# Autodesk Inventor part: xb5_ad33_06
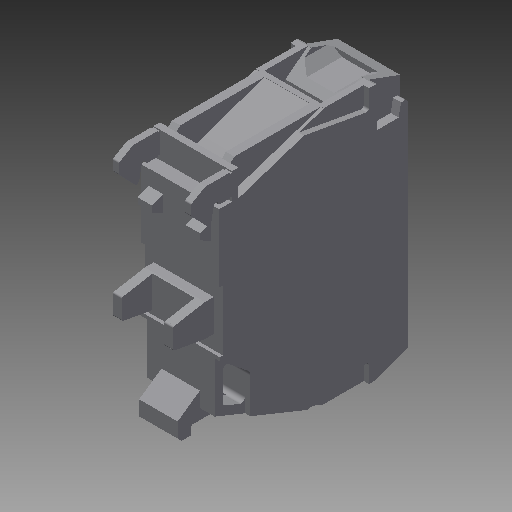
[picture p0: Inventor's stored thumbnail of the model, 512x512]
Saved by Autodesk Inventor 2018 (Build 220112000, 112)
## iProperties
Company: TraceParts S.A.
Created: 2018-05
Part Number: xb5_ad33_06
Checked By: TraceParts S.A.
Material: Generic
Catalog Web Link: www.traceparts.com
Document SubType Name: Modeling
Designer: TraceParts
Density: 1 g/cm^3
Appearance: Default
Author: TraceParts
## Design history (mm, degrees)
feature "xb5_ad33_06.ipt"
body "Solid1"
